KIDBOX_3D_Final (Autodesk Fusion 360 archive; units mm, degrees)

design "KIDBOX_SELECT_START_posicionados_Cabeza2mm"
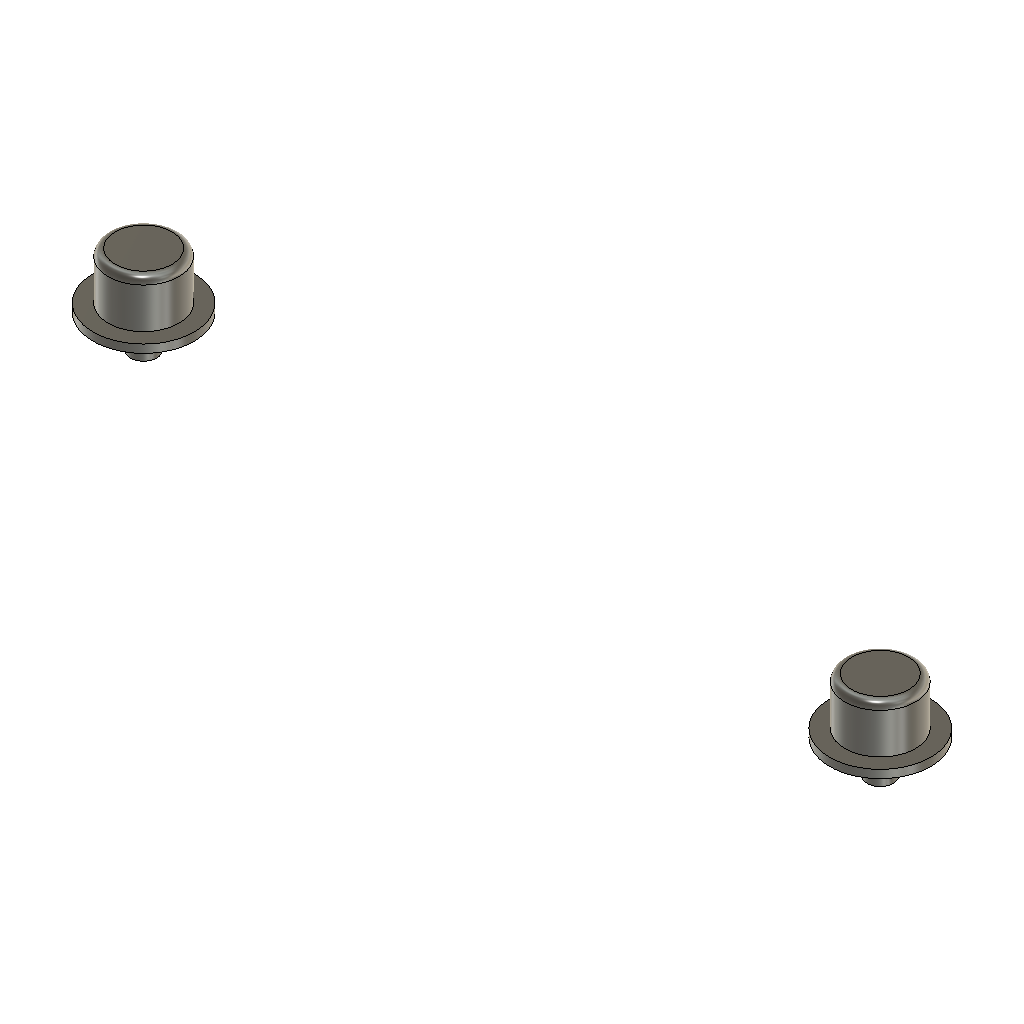
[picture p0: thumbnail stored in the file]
description: Open CASCADE Model
part number: KIDBOX_SELECT_START_ubicacion
description: Part Number
part number: SELECT
part number: START
base_feature "Base Feature1"
base_feature "Base Feature1"
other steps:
create_component "CreateComponent1"
create_component "CreateComponent2"

design "KIDBOX_Boton_AB_posicionado"
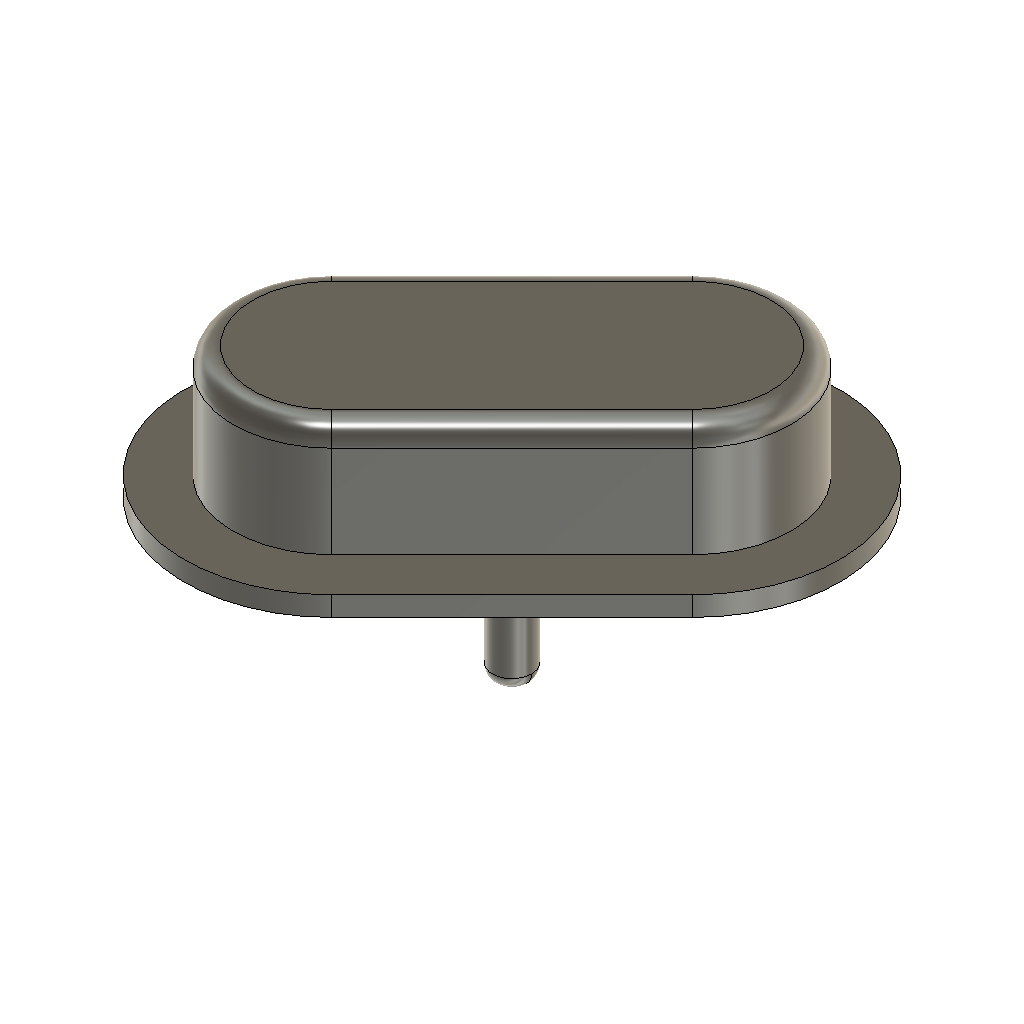
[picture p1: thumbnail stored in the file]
description: Open CASCADE Model
part number: KIDBOX_Botones_AB_posicionados
description: Part Number
part number: Balancin_AB
base_feature "Base Feature"
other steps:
create_component "CreateComponent1"

design "KIDBOX_Cruceta_Direccional_posicionada"
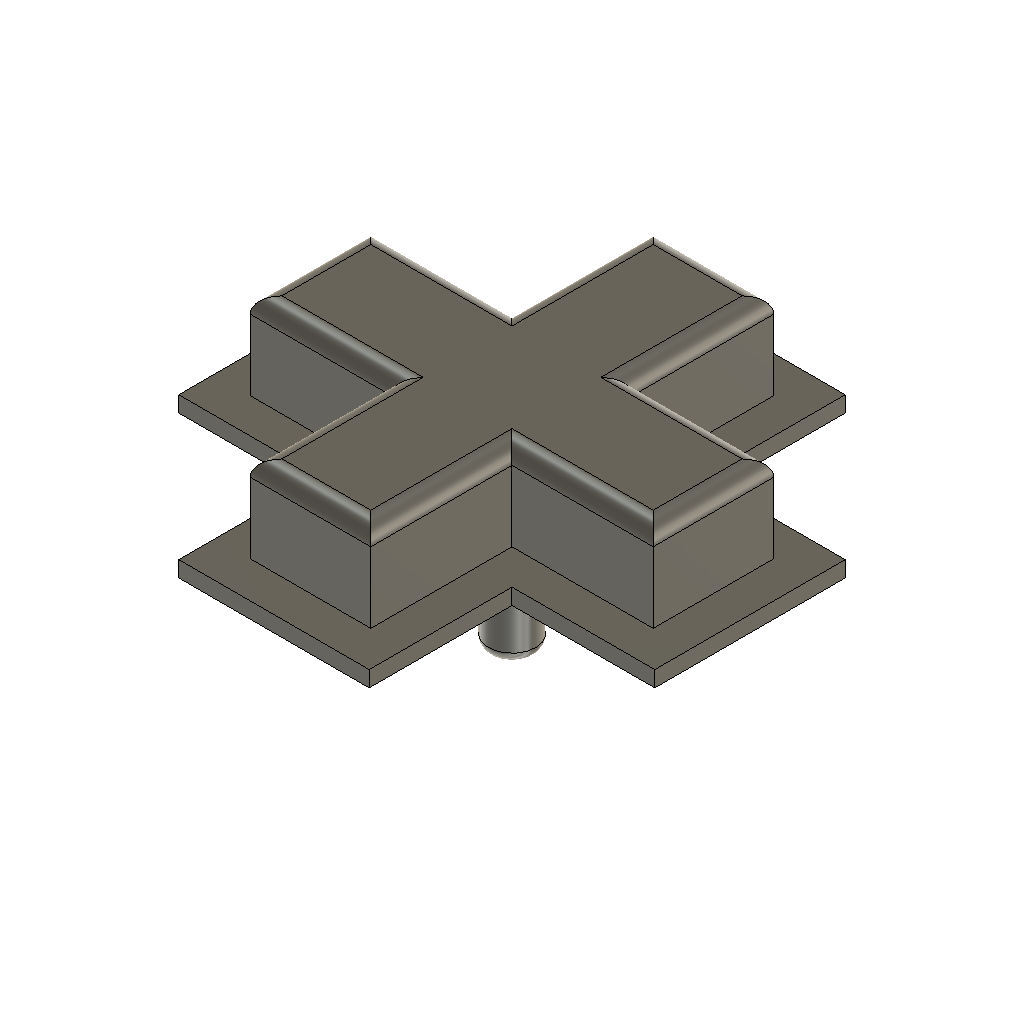
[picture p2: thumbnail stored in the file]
description: Open CASCADE Model
part number: KIDBOX_Cruceta_Direccional_Posicionada
description: Part Number
part number: Cruceta_UP_DOWN_LEFT_RIGHT
base_feature "Base Feature"
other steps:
create_component "CreateComponent1"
